# Generated by FakeRAM 2.0
VERSION 5.7 ;
BUSBITCHARS "[]" ;
PROPERTYDEFINITIONS
  MACRO width INTEGER ;
  MACRO depth INTEGER ;
  MACRO banks INTEGER ;
END PROPERTYDEFINITIONS
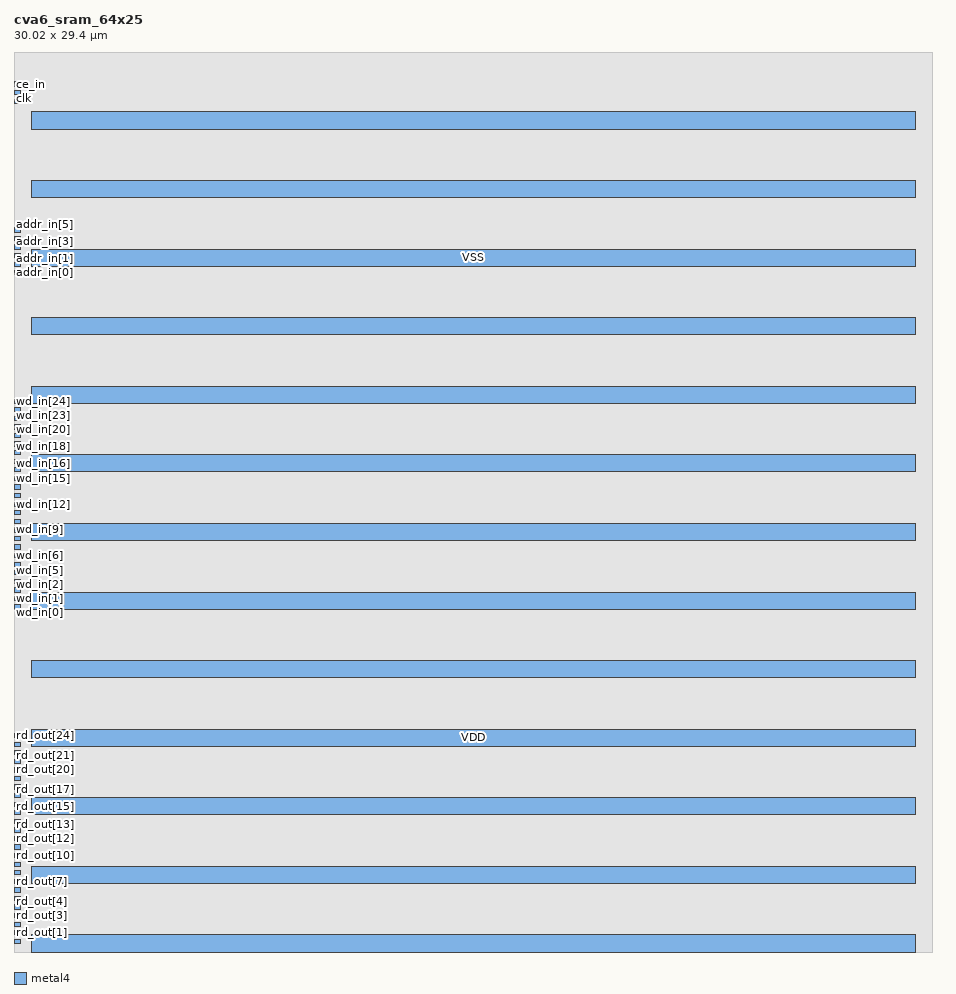
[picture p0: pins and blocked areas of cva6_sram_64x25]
MACRO cva6_sram_64x25
  PROPERTY width 25 ;
  PROPERTY depth 64 ;
  PROPERTY banks 1 ;
  FOREIGN cva6_sram_64x25 0 0 ;
  SYMMETRY X Y R90 ;
  SIZE 30.0200 BY 29.4000 ;
  CLASS BLOCK ;
  PIN rd_out[0]
    DIRECTION OUTPUT ;
    USE SIGNAL ;
    PORT
      LAYER metal4 ;
      RECT 0.00000 0.28000 0.21000 0.42000 ;
    END
  END rd_out[0]
  PIN rd_out[1]
    DIRECTION OUTPUT ;
    USE SIGNAL ;
    PORT
      LAYER metal4 ;
      RECT 0.00000 0.56000 0.21000 0.70000 ;
    END
  END rd_out[1]
  PIN rd_out[2]
    DIRECTION OUTPUT ;
    USE SIGNAL ;
    PORT
      LAYER metal4 ;
      RECT 0.00000 0.84000 0.21000 0.98000 ;
    END
  END rd_out[2]
  PIN rd_out[3]
    DIRECTION OUTPUT ;
    USE SIGNAL ;
    PORT
      LAYER metal4 ;
      RECT 0.00000 1.12000 0.21000 1.26000 ;
    END
  END rd_out[3]
  PIN rd_out[4]
    DIRECTION OUTPUT ;
    USE SIGNAL ;
    PORT
      LAYER metal4 ;
      RECT 0.00000 1.40000 0.21000 1.54000 ;
    END
  END rd_out[4]
  PIN rd_out[5]
    DIRECTION OUTPUT ;
    USE SIGNAL ;
    PORT
      LAYER metal4 ;
      RECT 0.00000 1.68000 0.21000 1.82000 ;
    END
  END rd_out[5]
  PIN rd_out[6]
    DIRECTION OUTPUT ;
    USE SIGNAL ;
    PORT
      LAYER metal4 ;
      RECT 0.00000 1.96000 0.21000 2.10000 ;
    END
  END rd_out[6]
  PIN rd_out[7]
    DIRECTION OUTPUT ;
    USE SIGNAL ;
    PORT
      LAYER metal4 ;
      RECT 0.00000 2.24000 0.21000 2.38000 ;
    END
  END rd_out[7]
  PIN rd_out[8]
    DIRECTION OUTPUT ;
    USE SIGNAL ;
    PORT
      LAYER metal4 ;
      RECT 0.00000 2.52000 0.21000 2.66000 ;
    END
  END rd_out[8]
  PIN rd_out[9]
    DIRECTION OUTPUT ;
    USE SIGNAL ;
    PORT
      LAYER metal4 ;
      RECT 0.00000 2.80000 0.21000 2.94000 ;
    END
  END rd_out[9]
  PIN rd_out[10]
    DIRECTION OUTPUT ;
    USE SIGNAL ;
    PORT
      LAYER metal4 ;
      RECT 0.00000 3.08000 0.21000 3.22000 ;
    END
  END rd_out[10]
  PIN rd_out[11]
    DIRECTION OUTPUT ;
    USE SIGNAL ;
    PORT
      LAYER metal4 ;
      RECT 0.00000 3.36000 0.21000 3.50000 ;
    END
  END rd_out[11]
  PIN rd_out[12]
    DIRECTION OUTPUT ;
    USE SIGNAL ;
    PORT
      LAYER metal4 ;
      RECT 0.00000 3.64000 0.21000 3.78000 ;
    END
  END rd_out[12]
  PIN rd_out[13]
    DIRECTION OUTPUT ;
    USE SIGNAL ;
    PORT
      LAYER metal4 ;
      RECT 0.00000 3.92000 0.21000 4.06000 ;
    END
  END rd_out[13]
  PIN rd_out[14]
    DIRECTION OUTPUT ;
    USE SIGNAL ;
    PORT
      LAYER metal4 ;
      RECT 0.00000 4.20000 0.21000 4.34000 ;
    END
  END rd_out[14]
  PIN rd_out[15]
    DIRECTION OUTPUT ;
    USE SIGNAL ;
    PORT
      LAYER metal4 ;
      RECT 0.00000 4.48000 0.21000 4.62000 ;
    END
  END rd_out[15]
  PIN rd_out[16]
    DIRECTION OUTPUT ;
    USE SIGNAL ;
    PORT
      LAYER metal4 ;
      RECT 0.00000 4.76000 0.21000 4.90000 ;
    END
  END rd_out[16]
  PIN rd_out[17]
    DIRECTION OUTPUT ;
    USE SIGNAL ;
    PORT
      LAYER metal4 ;
      RECT 0.00000 5.04000 0.21000 5.18000 ;
    END
  END rd_out[17]
  PIN rd_out[18]
    DIRECTION OUTPUT ;
    USE SIGNAL ;
    PORT
      LAYER metal4 ;
      RECT 0.00000 5.32000 0.21000 5.46000 ;
    END
  END rd_out[18]
  PIN rd_out[19]
    DIRECTION OUTPUT ;
    USE SIGNAL ;
    PORT
      LAYER metal4 ;
      RECT 0.00000 5.60000 0.21000 5.74000 ;
    END
  END rd_out[19]
  PIN rd_out[20]
    DIRECTION OUTPUT ;
    USE SIGNAL ;
    PORT
      LAYER metal4 ;
      RECT 0.00000 5.88000 0.21000 6.02000 ;
    END
  END rd_out[20]
  PIN rd_out[21]
    DIRECTION OUTPUT ;
    USE SIGNAL ;
    PORT
      LAYER metal4 ;
      RECT 0.00000 6.16000 0.21000 6.30000 ;
    END
  END rd_out[21]
  PIN rd_out[22]
    DIRECTION OUTPUT ;
    USE SIGNAL ;
    PORT
      LAYER metal4 ;
      RECT 0.00000 6.44000 0.21000 6.58000 ;
    END
  END rd_out[22]
  PIN rd_out[23]
    DIRECTION OUTPUT ;
    USE SIGNAL ;
    PORT
      LAYER metal4 ;
      RECT 0.00000 6.72000 0.21000 6.86000 ;
    END
  END rd_out[23]
  PIN rd_out[24]
    DIRECTION OUTPUT ;
    USE SIGNAL ;
    PORT
      LAYER metal4 ;
      RECT 0.00000 7.00000 0.21000 7.14000 ;
    END
  END rd_out[24]
  PIN wd_in[0]
    DIRECTION INPUT ;
    USE SIGNAL ;
    PORT
      LAYER metal4 ;
      RECT 0.00000 11.20000 0.21000 11.34000 ;
    END
  END wd_in[0]
  PIN wd_in[1]
    DIRECTION INPUT ;
    USE SIGNAL ;
    PORT
      LAYER metal4 ;
      RECT 0.00000 11.48000 0.21000 11.62000 ;
    END
  END wd_in[1]
  PIN wd_in[2]
    DIRECTION INPUT ;
    USE SIGNAL ;
    PORT
      LAYER metal4 ;
      RECT 0.00000 11.76000 0.21000 11.90000 ;
    END
  END wd_in[2]
  PIN wd_in[3]
    DIRECTION INPUT ;
    USE SIGNAL ;
    PORT
      LAYER metal4 ;
      RECT 0.00000 12.04000 0.21000 12.18000 ;
    END
  END wd_in[3]
  PIN wd_in[4]
    DIRECTION INPUT ;
    USE SIGNAL ;
    PORT
      LAYER metal4 ;
      RECT 0.00000 12.32000 0.21000 12.46000 ;
    END
  END wd_in[4]
  PIN wd_in[5]
    DIRECTION INPUT ;
    USE SIGNAL ;
    PORT
      LAYER metal4 ;
      RECT 0.00000 12.60000 0.21000 12.74000 ;
    END
  END wd_in[5]
  PIN wd_in[6]
    DIRECTION INPUT ;
    USE SIGNAL ;
    PORT
      LAYER metal4 ;
      RECT 0.00000 12.88000 0.21000 13.02000 ;
    END
  END wd_in[6]
  PIN wd_in[7]
    DIRECTION INPUT ;
    USE SIGNAL ;
    PORT
      LAYER metal4 ;
      RECT 0.00000 13.16000 0.21000 13.30000 ;
    END
  END wd_in[7]
  PIN wd_in[8]
    DIRECTION INPUT ;
    USE SIGNAL ;
    PORT
      LAYER metal4 ;
      RECT 0.00000 13.44000 0.21000 13.58000 ;
    END
  END wd_in[8]
  PIN wd_in[9]
    DIRECTION INPUT ;
    USE SIGNAL ;
    PORT
      LAYER metal4 ;
      RECT 0.00000 13.72000 0.21000 13.86000 ;
    END
  END wd_in[9]
  PIN wd_in[10]
    DIRECTION INPUT ;
    USE SIGNAL ;
    PORT
      LAYER metal4 ;
      RECT 0.00000 14.00000 0.21000 14.14000 ;
    END
  END wd_in[10]
  PIN wd_in[11]
    DIRECTION INPUT ;
    USE SIGNAL ;
    PORT
      LAYER metal4 ;
      RECT 0.00000 14.28000 0.21000 14.42000 ;
    END
  END wd_in[11]
  PIN wd_in[12]
    DIRECTION INPUT ;
    USE SIGNAL ;
    PORT
      LAYER metal4 ;
      RECT 0.00000 14.56000 0.21000 14.70000 ;
    END
  END wd_in[12]
  PIN wd_in[13]
    DIRECTION INPUT ;
    USE SIGNAL ;
    PORT
      LAYER metal4 ;
      RECT 0.00000 14.84000 0.21000 14.98000 ;
    END
  END wd_in[13]
  PIN wd_in[14]
    DIRECTION INPUT ;
    USE SIGNAL ;
    PORT
      LAYER metal4 ;
      RECT 0.00000 15.12000 0.21000 15.26000 ;
    END
  END wd_in[14]
  PIN wd_in[15]
    DIRECTION INPUT ;
    USE SIGNAL ;
    PORT
      LAYER metal4 ;
      RECT 0.00000 15.40000 0.21000 15.54000 ;
    END
  END wd_in[15]
  PIN wd_in[16]
    DIRECTION INPUT ;
    USE SIGNAL ;
    PORT
      LAYER metal4 ;
      RECT 0.00000 15.68000 0.21000 15.82000 ;
    END
  END wd_in[16]
  PIN wd_in[17]
    DIRECTION INPUT ;
    USE SIGNAL ;
    PORT
      LAYER metal4 ;
      RECT 0.00000 15.96000 0.21000 16.10000 ;
    END
  END wd_in[17]
  PIN wd_in[18]
    DIRECTION INPUT ;
    USE SIGNAL ;
    PORT
      LAYER metal4 ;
      RECT 0.00000 16.24000 0.21000 16.38000 ;
    END
  END wd_in[18]
  PIN wd_in[19]
    DIRECTION INPUT ;
    USE SIGNAL ;
    PORT
      LAYER metal4 ;
      RECT 0.00000 16.52000 0.21000 16.66000 ;
    END
  END wd_in[19]
  PIN wd_in[20]
    DIRECTION INPUT ;
    USE SIGNAL ;
    PORT
      LAYER metal4 ;
      RECT 0.00000 16.80000 0.21000 16.94000 ;
    END
  END wd_in[20]
  PIN wd_in[21]
    DIRECTION INPUT ;
    USE SIGNAL ;
    PORT
      LAYER metal4 ;
      RECT 0.00000 17.08000 0.21000 17.22000 ;
    END
  END wd_in[21]
  PIN wd_in[22]
    DIRECTION INPUT ;
    USE SIGNAL ;
    PORT
      LAYER metal4 ;
      RECT 0.00000 17.36000 0.21000 17.50000 ;
    END
  END wd_in[22]
  PIN wd_in[23]
    DIRECTION INPUT ;
    USE SIGNAL ;
    PORT
      LAYER metal4 ;
      RECT 0.00000 17.64000 0.21000 17.78000 ;
    END
  END wd_in[23]
  PIN wd_in[24]
    DIRECTION INPUT ;
    USE SIGNAL ;
    PORT
      LAYER metal4 ;
      RECT 0.00000 17.92000 0.21000 18.06000 ;
    END
  END wd_in[24]
  PIN addr_in[0]
    DIRECTION INPUT ;
    USE SIGNAL ;
    PORT
      LAYER metal4 ;
      RECT 0.00000 22.12000 0.21000 22.26000 ;
    END
  END addr_in[0]
  PIN addr_in[1]
    DIRECTION INPUT ;
    USE SIGNAL ;
    PORT
      LAYER metal4 ;
      RECT 0.00000 22.40000 0.21000 22.54000 ;
    END
  END addr_in[1]
  PIN addr_in[2]
    DIRECTION INPUT ;
    USE SIGNAL ;
    PORT
      LAYER metal4 ;
      RECT 0.00000 22.68000 0.21000 22.82000 ;
    END
  END addr_in[2]
  PIN addr_in[3]
    DIRECTION INPUT ;
    USE SIGNAL ;
    PORT
      LAYER metal4 ;
      RECT 0.00000 22.96000 0.21000 23.10000 ;
    END
  END addr_in[3]
  PIN addr_in[4]
    DIRECTION INPUT ;
    USE SIGNAL ;
    PORT
      LAYER metal4 ;
      RECT 0.00000 23.24000 0.21000 23.38000 ;
    END
  END addr_in[4]
  PIN addr_in[5]
    DIRECTION INPUT ;
    USE SIGNAL ;
    PORT
      LAYER metal4 ;
      RECT 0.00000 23.52000 0.21000 23.66000 ;
    END
  END addr_in[5]
  PIN we_in
    DIRECTION INPUT ;
    USE SIGNAL ;
    PORT
      LAYER metal4 ;
      RECT 0.00000 27.72000 0.21000 27.86000 ;
    END
  END we_in
  PIN clk
    DIRECTION INPUT ;
    USE SIGNAL ;
    PORT
      LAYER metal4 ;
      RECT 0.00000 28.00000 0.21000 28.14000 ;
    END
  END clk
  PIN ce_in
    DIRECTION INPUT ;
    USE SIGNAL ;
    PORT
      LAYER metal4 ;
      RECT 0.00000 28.28000 0.21000 28.42000 ;
    END
  END ce_in
  PIN VDD
    DIRECTION INOUT ;
    USE POWER ;
    PORT
      LAYER metal4 ;
      RECT 0.56000 2.24000 29.46000 2.80000 ;
      RECT 0.56000 6.72000 29.46000 7.28000 ;
      RECT 0.56000 11.20000 29.46000 11.76000 ;
      RECT 0.56000 15.68000 29.46000 16.24000 ;
      RECT 0.56000 20.16000 29.46000 20.72000 ;
      RECT 0.56000 24.64000 29.46000 25.20000 ;
    END
  END VDD
  PIN VSS
    DIRECTION INOUT ;
    USE GROUND ;
    PORT
      LAYER metal4 ;
      RECT 0.56000 0.00000 29.46000 0.56000 ;
      RECT 0.56000 4.48000 29.46000 5.04000 ;
      RECT 0.56000 8.96000 29.46000 9.52000 ;
      RECT 0.56000 13.44000 29.46000 14.00000 ;
      RECT 0.56000 17.92000 29.46000 18.48000 ;
      RECT 0.56000 22.40000 29.46000 22.96000 ;
      RECT 0.56000 26.88000 29.46000 27.44000 ;
    END
  END VSS
  OBS
    LAYER metal1 ;
    RECT 0 0 30.02000 29.40000 ;
    LAYER metal2 ;
    RECT 0 0 30.02000 29.40000 ;
    LAYER metal3 ;
    RECT 0 0 30.02000 29.40000 ;
    LAYER metal4 ;
    RECT 0 0 30.02000 29.40000 ;
  END
END cva6_sram_64x25

END LIBRARY
